VERSION 5.7 ;
  NOWIREEXTENSIONATPIN ON ;
  DIVIDERCHAR "/" ;
  BUSBITCHARS "[]" ;
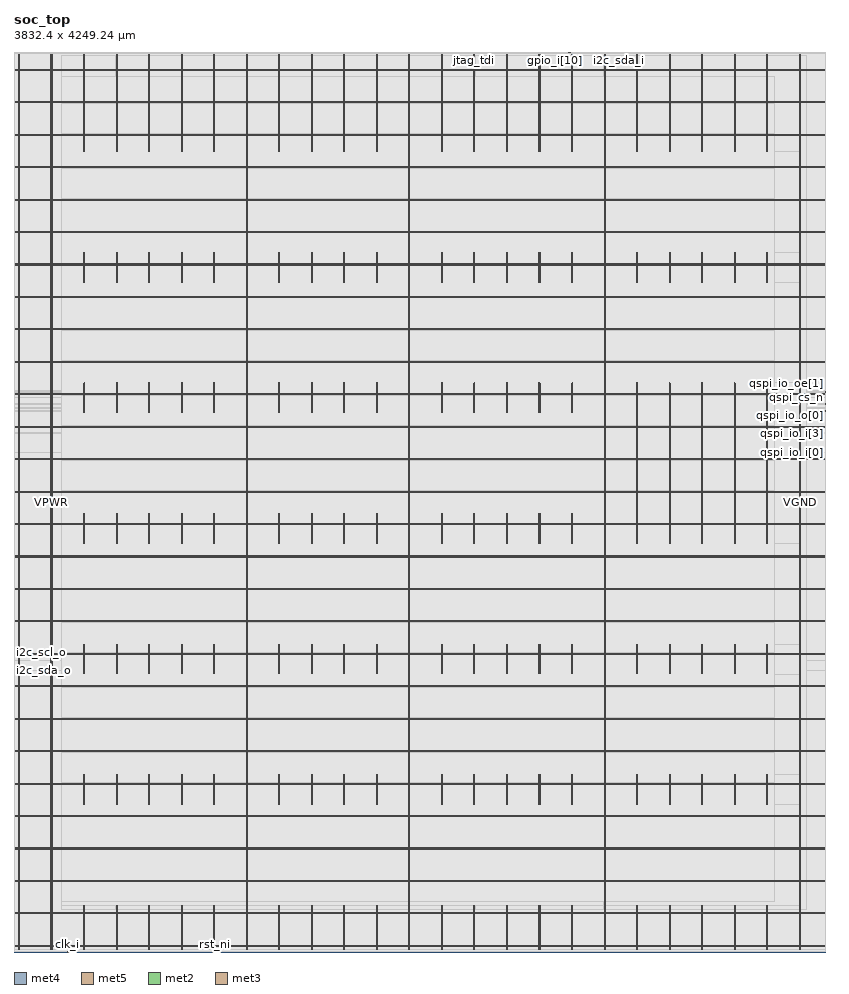
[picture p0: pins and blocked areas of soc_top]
MACRO soc_top
  CLASS BLOCK ;
  FOREIGN soc_top ;
  ORIGIN 0.000 0.000 ;
  SIZE 3832.400 BY 4249.240 ;
  PIN VGND
    DIRECTION INOUT ;
    USE GROUND ;
    PORT
      LAYER met4 ;
        RECT 24.340 10.640 25.940 4238.000 ;
    END
    PORT
      LAYER met4 ;
        RECT 177.940 10.640 179.540 4238.000 ;
    END
    PORT
      LAYER met4 ;
        RECT 331.540 10.640 333.140 220.320 ;
    END
    PORT
      LAYER met4 ;
        RECT 331.540 696.220 333.140 836.860 ;
    END
    PORT
      LAYER met4 ;
        RECT 331.540 1312.760 333.140 1453.400 ;
    END
    PORT
      LAYER met4 ;
        RECT 331.540 1929.300 333.140 2069.940 ;
    END
    PORT
      LAYER met4 ;
        RECT 331.540 2545.840 333.140 2686.480 ;
    END
    PORT
      LAYER met4 ;
        RECT 331.540 3162.380 333.140 3303.020 ;
    END
    PORT
      LAYER met4 ;
        RECT 331.540 3778.920 333.140 4238.000 ;
    END
    PORT
      LAYER met4 ;
        RECT 485.140 10.640 486.740 220.320 ;
    END
    PORT
      LAYER met4 ;
        RECT 485.140 696.220 486.740 836.860 ;
    END
    PORT
      LAYER met4 ;
        RECT 485.140 1312.760 486.740 1453.400 ;
    END
    PORT
      LAYER met4 ;
        RECT 485.140 1929.300 486.740 2069.940 ;
    END
    PORT
      LAYER met4 ;
        RECT 485.140 2545.840 486.740 2686.480 ;
    END
    PORT
      LAYER met4 ;
        RECT 485.140 3162.380 486.740 3303.020 ;
    END
    PORT
      LAYER met4 ;
        RECT 485.140 3778.920 486.740 4238.000 ;
    END
    PORT
      LAYER met4 ;
        RECT 638.740 10.640 640.340 220.320 ;
    END
    PORT
      LAYER met4 ;
        RECT 638.740 696.220 640.340 836.860 ;
    END
    PORT
      LAYER met4 ;
        RECT 638.740 1312.760 640.340 1453.400 ;
    END
    PORT
      LAYER met4 ;
        RECT 638.740 1929.300 640.340 2069.940 ;
    END
    PORT
      LAYER met4 ;
        RECT 638.740 2545.840 640.340 2686.480 ;
    END
    PORT
      LAYER met4 ;
        RECT 638.740 3162.380 640.340 3303.020 ;
    END
    PORT
      LAYER met4 ;
        RECT 638.740 3778.920 640.340 4238.000 ;
    END
    PORT
      LAYER met4 ;
        RECT 792.340 10.640 793.940 220.320 ;
    END
    PORT
      LAYER met4 ;
        RECT 792.340 696.220 793.940 836.860 ;
    END
    PORT
      LAYER met4 ;
        RECT 792.340 1312.760 793.940 1453.400 ;
    END
    PORT
      LAYER met4 ;
        RECT 792.340 1929.300 793.940 2069.940 ;
    END
    PORT
      LAYER met4 ;
        RECT 792.340 2545.840 793.940 2686.480 ;
    END
    PORT
      LAYER met4 ;
        RECT 792.340 3162.380 793.940 3303.020 ;
    END
    PORT
      LAYER met4 ;
        RECT 792.340 3778.920 793.940 4238.000 ;
    END
    PORT
      LAYER met4 ;
        RECT 945.940 10.640 947.540 220.320 ;
    END
    PORT
      LAYER met4 ;
        RECT 945.940 696.220 947.540 836.860 ;
    END
    PORT
      LAYER met4 ;
        RECT 945.940 1312.760 947.540 1453.400 ;
    END
    PORT
      LAYER met4 ;
        RECT 945.940 1929.300 947.540 2069.940 ;
    END
    PORT
      LAYER met4 ;
        RECT 945.940 2545.840 947.540 2686.480 ;
    END
    PORT
      LAYER met4 ;
        RECT 945.940 3162.380 947.540 3303.020 ;
    END
    PORT
      LAYER met4 ;
        RECT 945.940 3778.920 947.540 4238.000 ;
    END
    PORT
      LAYER met4 ;
        RECT 1099.540 10.640 1101.140 4238.000 ;
    END
    PORT
      LAYER met4 ;
        RECT 1253.140 10.640 1254.740 219.400 ;
    END
    PORT
      LAYER met4 ;
        RECT 1253.140 696.220 1254.740 835.940 ;
    END
    PORT
      LAYER met4 ;
        RECT 1253.140 1312.760 1254.740 1452.720 ;
    END
    PORT
      LAYER met4 ;
        RECT 1253.140 1929.300 1254.740 2069.020 ;
    END
    PORT
      LAYER met4 ;
        RECT 1253.140 2545.840 1254.740 2685.560 ;
    END
    PORT
      LAYER met4 ;
        RECT 1253.140 3162.380 1254.740 3302.320 ;
    END
    PORT
      LAYER met4 ;
        RECT 1253.140 3778.920 1254.740 4238.000 ;
    END
    PORT
      LAYER met4 ;
        RECT 1406.740 10.640 1408.340 220.320 ;
    END
    PORT
      LAYER met4 ;
        RECT 1406.740 696.220 1408.340 836.860 ;
    END
    PORT
      LAYER met4 ;
        RECT 1406.740 1312.760 1408.340 1453.400 ;
    END
    PORT
      LAYER met4 ;
        RECT 1406.740 1929.300 1408.340 2069.940 ;
    END
    PORT
      LAYER met4 ;
        RECT 1406.740 2545.840 1408.340 2686.480 ;
    END
    PORT
      LAYER met4 ;
        RECT 1406.740 3162.380 1408.340 3303.020 ;
    END
    PORT
      LAYER met4 ;
        RECT 1406.740 3778.920 1408.340 4238.000 ;
    END
    PORT
      LAYER met4 ;
        RECT 1560.340 10.640 1561.940 220.320 ;
    END
    PORT
      LAYER met4 ;
        RECT 1560.340 696.220 1561.940 836.860 ;
    END
    PORT
      LAYER met4 ;
        RECT 1560.340 1312.760 1561.940 1453.400 ;
    END
    PORT
      LAYER met4 ;
        RECT 1560.340 1929.300 1561.940 2069.940 ;
    END
    PORT
      LAYER met4 ;
        RECT 1560.340 2545.840 1561.940 2686.480 ;
    END
    PORT
      LAYER met4 ;
        RECT 1560.340 3162.380 1561.940 3303.020 ;
    END
    PORT
      LAYER met4 ;
        RECT 1560.340 3778.920 1561.940 4238.000 ;
    END
    PORT
      LAYER met4 ;
        RECT 1713.940 10.640 1715.540 220.320 ;
    END
    PORT
      LAYER met4 ;
        RECT 1713.940 696.220 1715.540 836.860 ;
    END
    PORT
      LAYER met4 ;
        RECT 1713.940 1312.760 1715.540 1453.400 ;
    END
    PORT
      LAYER met4 ;
        RECT 1713.940 1929.300 1715.540 2069.940 ;
    END
    PORT
      LAYER met4 ;
        RECT 1713.940 2545.840 1715.540 2686.480 ;
    END
    PORT
      LAYER met4 ;
        RECT 1713.940 3162.380 1715.540 3303.020 ;
    END
    PORT
      LAYER met4 ;
        RECT 1713.940 3778.920 1715.540 4238.000 ;
    END
    PORT
      LAYER met4 ;
        RECT 1867.540 10.640 1869.140 4238.000 ;
    END
    PORT
      LAYER met4 ;
        RECT 2021.140 10.640 2022.740 220.320 ;
    END
    PORT
      LAYER met4 ;
        RECT 2021.140 696.220 2022.740 836.860 ;
    END
    PORT
      LAYER met4 ;
        RECT 2021.140 1312.760 2022.740 1453.400 ;
    END
    PORT
      LAYER met4 ;
        RECT 2021.140 1929.300 2022.740 2069.940 ;
    END
    PORT
      LAYER met4 ;
        RECT 2021.140 2545.840 2022.740 2686.480 ;
    END
    PORT
      LAYER met4 ;
        RECT 2021.140 3162.380 2022.740 3303.020 ;
    END
    PORT
      LAYER met4 ;
        RECT 2021.140 3778.920 2022.740 4238.000 ;
    END
    PORT
      LAYER met4 ;
        RECT 2174.740 10.640 2176.340 220.320 ;
    END
    PORT
      LAYER met4 ;
        RECT 2174.740 696.220 2176.340 836.860 ;
    END
    PORT
      LAYER met4 ;
        RECT 2174.740 1312.760 2176.340 1453.400 ;
    END
    PORT
      LAYER met4 ;
        RECT 2174.740 1929.300 2176.340 2069.940 ;
    END
    PORT
      LAYER met4 ;
        RECT 2174.740 2545.840 2176.340 2686.480 ;
    END
    PORT
      LAYER met4 ;
        RECT 2174.740 3162.380 2176.340 3303.020 ;
    END
    PORT
      LAYER met4 ;
        RECT 2174.740 3778.920 2176.340 4238.000 ;
    END
    PORT
      LAYER met4 ;
        RECT 2328.340 10.640 2329.940 220.320 ;
    END
    PORT
      LAYER met4 ;
        RECT 2328.340 696.220 2329.940 836.860 ;
    END
    PORT
      LAYER met4 ;
        RECT 2328.340 1312.760 2329.940 1453.400 ;
    END
    PORT
      LAYER met4 ;
        RECT 2328.340 1929.300 2329.940 2069.940 ;
    END
    PORT
      LAYER met4 ;
        RECT 2328.340 2545.840 2329.940 2686.480 ;
    END
    PORT
      LAYER met4 ;
        RECT 2328.340 3162.380 2329.940 3303.020 ;
    END
    PORT
      LAYER met4 ;
        RECT 2328.340 3778.920 2329.940 4238.000 ;
    END
    PORT
      LAYER met4 ;
        RECT 2481.940 10.640 2483.540 219.400 ;
    END
    PORT
      LAYER met4 ;
        RECT 2481.940 697.140 2483.540 835.940 ;
    END
    PORT
      LAYER met4 ;
        RECT 2481.940 1313.680 2483.540 1452.720 ;
    END
    PORT
      LAYER met4 ;
        RECT 2481.940 1930.220 2483.540 2069.020 ;
    END
    PORT
      LAYER met4 ;
        RECT 2481.940 2546.760 2483.540 2685.560 ;
    END
    PORT
      LAYER met4 ;
        RECT 2481.940 3163.300 2483.540 3302.320 ;
    END
    PORT
      LAYER met4 ;
        RECT 2481.940 3779.840 2483.540 4238.000 ;
    END
    PORT
      LAYER met4 ;
        RECT 2635.540 10.640 2637.140 220.320 ;
    END
    PORT
      LAYER met4 ;
        RECT 2635.540 696.220 2637.140 836.860 ;
    END
    PORT
      LAYER met4 ;
        RECT 2635.540 1312.760 2637.140 1453.400 ;
    END
    PORT
      LAYER met4 ;
        RECT 2635.540 1929.300 2637.140 2069.940 ;
    END
    PORT
      LAYER met4 ;
        RECT 2635.540 2545.840 2637.140 2686.480 ;
    END
    PORT
      LAYER met4 ;
        RECT 2635.540 3162.380 2637.140 3303.020 ;
    END
    PORT
      LAYER met4 ;
        RECT 2635.540 3778.920 2637.140 4238.000 ;
    END
    PORT
      LAYER met4 ;
        RECT 2789.140 10.640 2790.740 4238.000 ;
    END
    PORT
      LAYER met4 ;
        RECT 2942.740 10.640 2944.340 220.320 ;
    END
    PORT
      LAYER met4 ;
        RECT 2942.740 696.220 2944.340 836.860 ;
    END
    PORT
      LAYER met4 ;
        RECT 2942.740 1312.760 2944.340 1453.400 ;
    END
    PORT
      LAYER met4 ;
        RECT 2942.740 1929.300 2944.340 2686.480 ;
    END
    PORT
      LAYER met4 ;
        RECT 2942.740 3162.380 2944.340 3303.020 ;
    END
    PORT
      LAYER met4 ;
        RECT 2942.740 3778.920 2944.340 4238.000 ;
    END
    PORT
      LAYER met4 ;
        RECT 3096.340 10.640 3097.940 219.400 ;
    END
    PORT
      LAYER met4 ;
        RECT 3096.340 696.220 3097.940 835.940 ;
    END
    PORT
      LAYER met4 ;
        RECT 3096.340 1312.760 3097.940 1452.720 ;
    END
    PORT
      LAYER met4 ;
        RECT 3096.340 1929.300 3097.940 2685.560 ;
    END
    PORT
      LAYER met4 ;
        RECT 3096.340 3162.380 3097.940 3302.320 ;
    END
    PORT
      LAYER met4 ;
        RECT 3096.340 3778.920 3097.940 4238.000 ;
    END
    PORT
      LAYER met4 ;
        RECT 3249.940 10.640 3251.540 220.320 ;
    END
    PORT
      LAYER met4 ;
        RECT 3249.940 696.220 3251.540 836.860 ;
    END
    PORT
      LAYER met4 ;
        RECT 3249.940 1312.760 3251.540 1453.400 ;
    END
    PORT
      LAYER met4 ;
        RECT 3249.940 1929.300 3251.540 2686.480 ;
    END
    PORT
      LAYER met4 ;
        RECT 3249.940 3162.380 3251.540 3303.020 ;
    END
    PORT
      LAYER met4 ;
        RECT 3249.940 3778.920 3251.540 4238.000 ;
    END
    PORT
      LAYER met4 ;
        RECT 3403.540 10.640 3405.140 219.400 ;
    END
    PORT
      LAYER met4 ;
        RECT 3403.540 697.140 3405.140 835.940 ;
    END
    PORT
      LAYER met4 ;
        RECT 3403.540 1313.680 3405.140 1452.720 ;
    END
    PORT
      LAYER met4 ;
        RECT 3403.540 1930.220 3405.140 2685.560 ;
    END
    PORT
      LAYER met4 ;
        RECT 3403.540 3163.300 3405.140 3302.320 ;
    END
    PORT
      LAYER met4 ;
        RECT 3403.540 3779.840 3405.140 4238.000 ;
    END
    PORT
      LAYER met4 ;
        RECT 3557.140 10.640 3558.740 220.320 ;
    END
    PORT
      LAYER met4 ;
        RECT 3557.140 696.220 3558.740 836.860 ;
    END
    PORT
      LAYER met4 ;
        RECT 3557.140 1312.760 3558.740 1453.400 ;
    END
    PORT
      LAYER met4 ;
        RECT 3557.140 1929.300 3558.740 2686.480 ;
    END
    PORT
      LAYER met4 ;
        RECT 3557.140 3162.380 3558.740 3303.020 ;
    END
    PORT
      LAYER met4 ;
        RECT 3557.140 3778.920 3558.740 4238.000 ;
    END
    PORT
      LAYER met4 ;
        RECT 3710.740 10.640 3712.340 4238.000 ;
    END
    PORT
      LAYER met5 ;
        RECT 5.520 30.030 3826.740 31.630 ;
    END
    PORT
      LAYER met5 ;
        RECT 5.520 183.210 3826.740 184.810 ;
    END
    PORT
      LAYER met5 ;
        RECT 5.520 336.390 3826.740 337.990 ;
    END
    PORT
      LAYER met5 ;
        RECT 5.520 489.570 3826.740 491.170 ;
    END
    PORT
      LAYER met5 ;
        RECT 5.520 642.750 3826.740 644.350 ;
    END
    PORT
      LAYER met5 ;
        RECT 5.520 795.930 3826.740 797.530 ;
    END
    PORT
      LAYER met5 ;
        RECT 5.520 949.110 3826.740 950.710 ;
    END
    PORT
      LAYER met5 ;
        RECT 5.520 1102.290 3826.740 1103.890 ;
    END
    PORT
      LAYER met5 ;
        RECT 5.520 1255.470 3826.740 1257.070 ;
    END
    PORT
      LAYER met5 ;
        RECT 5.520 1408.650 3826.740 1410.250 ;
    END
    PORT
      LAYER met5 ;
        RECT 5.520 1561.830 3826.740 1563.430 ;
    END
    PORT
      LAYER met5 ;
        RECT 5.520 1715.010 3826.740 1716.610 ;
    END
    PORT
      LAYER met5 ;
        RECT 5.520 1868.190 3826.740 1869.790 ;
    END
    PORT
      LAYER met5 ;
        RECT 5.520 2021.370 3826.740 2022.970 ;
    END
    PORT
      LAYER met5 ;
        RECT 5.520 2174.550 3826.740 2176.150 ;
    END
    PORT
      LAYER met5 ;
        RECT 5.520 2327.730 3826.740 2329.330 ;
    END
    PORT
      LAYER met5 ;
        RECT 5.520 2480.910 3826.740 2482.510 ;
    END
    PORT
      LAYER met5 ;
        RECT 5.520 2634.090 3826.740 2635.690 ;
    END
    PORT
      LAYER met5 ;
        RECT 5.520 2787.270 3826.740 2788.870 ;
    END
    PORT
      LAYER met5 ;
        RECT 5.520 2940.450 3826.740 2942.050 ;
    END
    PORT
      LAYER met5 ;
        RECT 5.520 3093.630 3826.740 3095.230 ;
    END
    PORT
      LAYER met5 ;
        RECT 5.520 3246.810 3826.740 3248.410 ;
    END
    PORT
      LAYER met5 ;
        RECT 5.520 3399.990 3826.740 3401.590 ;
    END
    PORT
      LAYER met5 ;
        RECT 5.520 3553.170 3826.740 3554.770 ;
    END
    PORT
      LAYER met5 ;
        RECT 5.520 3706.350 3826.740 3707.950 ;
    END
    PORT
      LAYER met5 ;
        RECT 5.520 3859.530 3826.740 3861.130 ;
    END
    PORT
      LAYER met5 ;
        RECT 5.520 4012.710 3826.740 4014.310 ;
    END
    PORT
      LAYER met5 ;
        RECT 5.520 4165.890 3826.740 4167.490 ;
    END
  END VGND
  PIN VPWR
    DIRECTION INOUT ;
    USE POWER ;
    PORT
      LAYER met4 ;
        RECT 21.040 10.640 22.640 4238.000 ;
    END
    PORT
      LAYER met4 ;
        RECT 174.640 10.640 176.240 4238.000 ;
    END
    PORT
      LAYER met4 ;
        RECT 328.240 10.640 329.840 219.400 ;
    END
    PORT
      LAYER met4 ;
        RECT 328.240 696.220 329.840 835.940 ;
    END
    PORT
      LAYER met4 ;
        RECT 328.240 1312.760 329.840 1452.480 ;
    END
    PORT
      LAYER met4 ;
        RECT 328.240 1929.300 329.840 2069.020 ;
    END
    PORT
      LAYER met4 ;
        RECT 328.240 2545.840 329.840 2685.560 ;
    END
    PORT
      LAYER met4 ;
        RECT 328.240 3162.380 329.840 3302.100 ;
    END
    PORT
      LAYER met4 ;
        RECT 328.240 3778.920 329.840 4238.000 ;
    END
    PORT
      LAYER met4 ;
        RECT 481.840 10.640 483.440 219.400 ;
    END
    PORT
      LAYER met4 ;
        RECT 481.840 696.220 483.440 835.940 ;
    END
    PORT
      LAYER met4 ;
        RECT 481.840 1312.760 483.440 1452.480 ;
    END
    PORT
      LAYER met4 ;
        RECT 481.840 1929.300 483.440 2069.020 ;
    END
    PORT
      LAYER met4 ;
        RECT 481.840 2545.840 483.440 2685.560 ;
    END
    PORT
      LAYER met4 ;
        RECT 481.840 3162.380 483.440 3302.100 ;
    END
    PORT
      LAYER met4 ;
        RECT 481.840 3778.920 483.440 4238.000 ;
    END
    PORT
      LAYER met4 ;
        RECT 635.440 10.640 637.040 220.320 ;
    END
    PORT
      LAYER met4 ;
        RECT 635.440 696.220 637.040 836.860 ;
    END
    PORT
      LAYER met4 ;
        RECT 635.440 1312.760 637.040 1453.400 ;
    END
    PORT
      LAYER met4 ;
        RECT 635.440 1929.300 637.040 2069.940 ;
    END
    PORT
      LAYER met4 ;
        RECT 635.440 2545.840 637.040 2686.480 ;
    END
    PORT
      LAYER met4 ;
        RECT 635.440 3162.380 637.040 3303.020 ;
    END
    PORT
      LAYER met4 ;
        RECT 635.440 3778.920 637.040 4238.000 ;
    END
    PORT
      LAYER met4 ;
        RECT 789.040 10.640 790.640 220.320 ;
    END
    PORT
      LAYER met4 ;
        RECT 789.040 696.220 790.640 836.860 ;
    END
    PORT
      LAYER met4 ;
        RECT 789.040 1312.760 790.640 1453.400 ;
    END
    PORT
      LAYER met4 ;
        RECT 789.040 1929.300 790.640 2069.940 ;
    END
    PORT
      LAYER met4 ;
        RECT 789.040 2545.840 790.640 2686.480 ;
    END
    PORT
      LAYER met4 ;
        RECT 789.040 3162.380 790.640 3303.020 ;
    END
    PORT
      LAYER met4 ;
        RECT 789.040 3778.920 790.640 4238.000 ;
    END
    PORT
      LAYER met4 ;
        RECT 942.640 10.640 944.240 220.320 ;
    END
    PORT
      LAYER met4 ;
        RECT 942.640 696.220 944.240 836.860 ;
    END
    PORT
      LAYER met4 ;
        RECT 942.640 1312.760 944.240 1453.400 ;
    END
    PORT
      LAYER met4 ;
        RECT 942.640 1929.300 944.240 2069.940 ;
    END
    PORT
      LAYER met4 ;
        RECT 942.640 2545.840 944.240 2686.480 ;
    END
    PORT
      LAYER met4 ;
        RECT 942.640 3162.380 944.240 3303.020 ;
    END
    PORT
      LAYER met4 ;
        RECT 942.640 3778.920 944.240 4238.000 ;
    END
    PORT
      LAYER met4 ;
        RECT 1096.240 10.640 1097.840 4238.000 ;
    END
    PORT
      LAYER met4 ;
        RECT 1249.840 10.640 1251.440 220.320 ;
    END
    PORT
      LAYER met4 ;
        RECT 1249.840 696.220 1251.440 836.860 ;
    END
    PORT
      LAYER met4 ;
        RECT 1249.840 1312.760 1251.440 1453.400 ;
    END
    PORT
      LAYER met4 ;
        RECT 1249.840 1929.300 1251.440 2069.940 ;
    END
    PORT
      LAYER met4 ;
        RECT 1249.840 2545.840 1251.440 2686.480 ;
    END
    PORT
      LAYER met4 ;
        RECT 1249.840 3162.380 1251.440 3303.020 ;
    END
    PORT
      LAYER met4 ;
        RECT 1249.840 3778.920 1251.440 4238.000 ;
    END
    PORT
      LAYER met4 ;
        RECT 1403.440 10.640 1405.040 219.400 ;
    END
    PORT
      LAYER met4 ;
        RECT 1403.440 696.220 1405.040 835.940 ;
    END
    PORT
      LAYER met4 ;
        RECT 1403.440 1312.760 1405.040 1452.480 ;
    END
    PORT
      LAYER met4 ;
        RECT 1403.440 1929.300 1405.040 2069.020 ;
    END
    PORT
      LAYER met4 ;
        RECT 1403.440 2545.840 1405.040 2685.560 ;
    END
    PORT
      LAYER met4 ;
        RECT 1403.440 3162.380 1405.040 3302.100 ;
    END
    PORT
      LAYER met4 ;
        RECT 1403.440 3778.920 1405.040 4238.000 ;
    END
    PORT
      LAYER met4 ;
        RECT 1557.040 10.640 1558.640 220.320 ;
    END
    PORT
      LAYER met4 ;
        RECT 1557.040 696.220 1558.640 836.860 ;
    END
    PORT
      LAYER met4 ;
        RECT 1557.040 1312.760 1558.640 1453.400 ;
    END
    PORT
      LAYER met4 ;
        RECT 1557.040 1929.300 1558.640 2069.940 ;
    END
    PORT
      LAYER met4 ;
        RECT 1557.040 2545.840 1558.640 2686.480 ;
    END
    PORT
      LAYER met4 ;
        RECT 1557.040 3162.380 1558.640 3303.020 ;
    END
    PORT
      LAYER met4 ;
        RECT 1557.040 3778.920 1558.640 4238.000 ;
    END
    PORT
      LAYER met4 ;
        RECT 1710.640 10.640 1712.240 220.320 ;
    END
    PORT
      LAYER met4 ;
        RECT 1710.640 696.220 1712.240 836.860 ;
    END
    PORT
      LAYER met4 ;
        RECT 1710.640 1312.760 1712.240 1453.400 ;
    END
    PORT
      LAYER met4 ;
        RECT 1710.640 1929.300 1712.240 2069.940 ;
    END
    PORT
      LAYER met4 ;
        RECT 1710.640 2545.840 1712.240 2686.480 ;
    END
    PORT
      LAYER met4 ;
        RECT 1710.640 3162.380 1712.240 3303.020 ;
    END
    PORT
      LAYER met4 ;
        RECT 1710.640 3778.920 1712.240 4238.000 ;
    END
    PORT
      LAYER met4 ;
        RECT 1864.240 10.640 1865.840 4238.000 ;
    END
    PORT
      LAYER met4 ;
        RECT 2017.840 10.640 2019.440 220.320 ;
    END
    PORT
      LAYER met4 ;
        RECT 2017.840 696.220 2019.440 836.860 ;
    END
    PORT
      LAYER met4 ;
        RECT 2017.840 1312.760 2019.440 1453.400 ;
    END
    PORT
      LAYER met4 ;
        RECT 2017.840 1929.300 2019.440 2069.940 ;
    END
    PORT
      LAYER met4 ;
        RECT 2017.840 2545.840 2019.440 2686.480 ;
    END
    PORT
      LAYER met4 ;
        RECT 2017.840 3162.380 2019.440 3303.020 ;
    END
    PORT
      LAYER met4 ;
        RECT 2017.840 3778.920 2019.440 4238.000 ;
    END
    PORT
      LAYER met4 ;
        RECT 2171.440 10.640 2173.040 219.400 ;
    END
    PORT
      LAYER met4 ;
        RECT 2171.440 697.140 2173.040 835.940 ;
    END
    PORT
      LAYER met4 ;
        RECT 2171.440 1313.520 2173.040 1452.480 ;
    END
    PORT
      LAYER met4 ;
        RECT 2171.440 1930.220 2173.040 2069.020 ;
    END
    PORT
      LAYER met4 ;
        RECT 2171.440 2546.760 2173.040 2685.560 ;
    END
    PORT
      LAYER met4 ;
        RECT 2171.440 3163.120 2173.040 3302.100 ;
    END
    PORT
      LAYER met4 ;
        RECT 2171.440 3779.840 2173.040 4238.000 ;
    END
    PORT
      LAYER met4 ;
        RECT 2325.040 10.640 2326.640 220.320 ;
    END
    PORT
      LAYER met4 ;
        RECT 2325.040 696.220 2326.640 836.860 ;
    END
    PORT
      LAYER met4 ;
        RECT 2325.040 1312.760 2326.640 1453.400 ;
    END
    PORT
      LAYER met4 ;
        RECT 2325.040 1929.300 2326.640 2069.940 ;
    END
    PORT
      LAYER met4 ;
        RECT 2325.040 2545.840 2326.640 2686.480 ;
    END
    PORT
      LAYER met4 ;
        RECT 2325.040 3162.380 2326.640 3303.020 ;
    END
    PORT
      LAYER met4 ;
        RECT 2325.040 3778.920 2326.640 4238.000 ;
    END
    PORT
      LAYER met4 ;
        RECT 2478.640 10.640 2480.240 220.320 ;
    END
    PORT
      LAYER met4 ;
        RECT 2478.640 696.220 2480.240 836.860 ;
    END
    PORT
      LAYER met4 ;
        RECT 2478.640 1312.760 2480.240 1453.400 ;
    END
    PORT
      LAYER met4 ;
        RECT 2478.640 1929.300 2480.240 2069.940 ;
    END
    PORT
      LAYER met4 ;
        RECT 2478.640 2545.840 2480.240 2686.480 ;
    END
    PORT
      LAYER met4 ;
        RECT 2478.640 3162.380 2480.240 3303.020 ;
    END
    PORT
      LAYER met4 ;
        RECT 2478.640 3778.920 2480.240 4238.000 ;
    END
    PORT
      LAYER met4 ;
        RECT 2632.240 10.640 2633.840 219.400 ;
    END
    PORT
      LAYER met4 ;
        RECT 2632.240 696.220 2633.840 835.940 ;
    END
    PORT
      LAYER met4 ;
        RECT 2632.240 1312.760 2633.840 1452.480 ;
    END
    PORT
      LAYER met4 ;
        RECT 2632.240 1929.300 2633.840 2069.020 ;
    END
    PORT
      LAYER met4 ;
        RECT 2632.240 2545.840 2633.840 2685.560 ;
    END
    PORT
      LAYER met4 ;
        RECT 2632.240 3162.380 2633.840 3302.100 ;
    END
    PORT
      LAYER met4 ;
        RECT 2632.240 3778.920 2633.840 4238.000 ;
    END
    PORT
      LAYER met4 ;
        RECT 2785.840 10.640 2787.440 4238.000 ;
    END
    PORT
      LAYER met4 ;
        RECT 2939.440 10.640 2941.040 220.320 ;
    END
    PORT
      LAYER met4 ;
        RECT 2939.440 696.220 2941.040 836.860 ;
    END
    PORT
      LAYER met4 ;
        RECT 2939.440 1312.760 2941.040 1453.400 ;
    END
    PORT
      LAYER met4 ;
        RECT 2939.440 1929.300 2941.040 2686.480 ;
    END
    PORT
      LAYER met4 ;
        RECT 2939.440 3162.380 2941.040 3303.020 ;
    END
    PORT
      LAYER met4 ;
        RECT 2939.440 3778.920 2941.040 4238.000 ;
    END
    PORT
      LAYER met4 ;
        RECT 3093.040 10.640 3094.640 220.320 ;
    END
    PORT
      LAYER met4 ;
        RECT 3093.040 696.220 3094.640 836.860 ;
    END
    PORT
      LAYER met4 ;
        RECT 3093.040 1312.760 3094.640 1453.400 ;
    END
    PORT
      LAYER met4 ;
        RECT 3093.040 1929.300 3094.640 2686.480 ;
    END
    PORT
      LAYER met4 ;
        RECT 3093.040 3162.380 3094.640 3303.020 ;
    END
    PORT
      LAYER met4 ;
        RECT 3093.040 3778.920 3094.640 4238.000 ;
    END
    PORT
      LAYER met4 ;
        RECT 3246.640 10.640 3248.240 220.320 ;
    END
    PORT
      LAYER met4 ;
        RECT 3246.640 696.220 3248.240 836.860 ;
    END
    PORT
      LAYER met4 ;
        RECT 3246.640 1312.760 3248.240 1453.400 ;
    END
    PORT
      LAYER met4 ;
        RECT 3246.640 1929.300 3248.240 2686.480 ;
    END
    PORT
      LAYER met4 ;
        RECT 3246.640 3162.380 3248.240 3303.020 ;
    END
    PORT
      LAYER met4 ;
        RECT 3246.640 3778.920 3248.240 4238.000 ;
    END
    PORT
      LAYER met4 ;
        RECT 3400.240 10.640 3401.840 220.320 ;
    END
    PORT
      LAYER met4 ;
        RECT 3400.240 696.220 3401.840 836.860 ;
    END
    PORT
      LAYER met4 ;
        RECT 3400.240 1312.760 3401.840 1453.400 ;
    END
    PORT
      LAYER met4 ;
        RECT 3400.240 1929.300 3401.840 2686.480 ;
    END
    PORT
      LAYER met4 ;
        RECT 3400.240 3162.380 3401.840 3303.020 ;
    END
    PORT
      LAYER met4 ;
        RECT 3400.240 3778.920 3401.840 4238.000 ;
    END
    PORT
      LAYER met4 ;
        RECT 3553.840 10.640 3555.440 220.320 ;
    END
    PORT
      LAYER met4 ;
        RECT 3553.840 697.140 3555.440 836.860 ;
    END
    PORT
      LAYER met4 ;
        RECT 3553.840 1313.520 3555.440 1453.400 ;
    END
    PORT
      LAYER met4 ;
        RECT 3553.840 1930.220 3555.440 2686.480 ;
    END
    PORT
      LAYER met4 ;
        RECT 3553.840 3163.120 3555.440 3303.020 ;
    END
    PORT
      LAYER met4 ;
        RECT 3553.840 3779.840 3555.440 4238.000 ;
    END
    PORT
      LAYER met4 ;
        RECT 3707.440 10.640 3709.040 4238.000 ;
    END
    PORT
      LAYER met5 ;
        RECT 5.520 26.730 3826.740 28.330 ;
    END
    PORT
      LAYER met5 ;
        RECT 5.520 179.910 3826.740 181.510 ;
    END
    PORT
      LAYER met5 ;
        RECT 5.520 333.090 3826.740 334.690 ;
    END
    PORT
      LAYER met5 ;
        RECT 5.520 486.270 3826.740 487.870 ;
    END
    PORT
      LAYER met5 ;
        RECT 5.520 639.450 3826.740 641.050 ;
    END
    PORT
      LAYER met5 ;
        RECT 5.520 792.630 3826.740 794.230 ;
    END
    PORT
      LAYER met5 ;
        RECT 5.520 945.810 3826.740 947.410 ;
    END
    PORT
      LAYER met5 ;
        RECT 5.520 1098.990 3826.740 1100.590 ;
    END
    PORT
      LAYER met5 ;
        RECT 5.520 1252.170 3826.740 1253.770 ;
    END
    PORT
      LAYER met5 ;
        RECT 5.520 1405.350 3826.740 1406.950 ;
    END
    PORT
      LAYER met5 ;
        RECT 5.520 1558.530 3826.740 1560.130 ;
    END
    PORT
      LAYER met5 ;
        RECT 5.520 1711.710 3826.740 1713.310 ;
    END
    PORT
      LAYER met5 ;
        RECT 5.520 1864.890 3826.740 1866.490 ;
    END
    PORT
      LAYER met5 ;
        RECT 5.520 2018.070 3826.740 2019.670 ;
    END
    PORT
      LAYER met5 ;
        RECT 5.520 2171.250 3826.740 2172.850 ;
    END
    PORT
      LAYER met5 ;
        RECT 5.520 2324.430 3826.740 2326.030 ;
    END
    PORT
      LAYER met5 ;
        RECT 5.520 2477.610 3826.740 2479.210 ;
    END
    PORT
      LAYER met5 ;
        RECT 5.520 2630.790 3826.740 2632.390 ;
    END
    PORT
      LAYER met5 ;
        RECT 5.520 2783.970 3826.740 2785.570 ;
    END
    PORT
      LAYER met5 ;
        RECT 5.520 2937.150 3826.740 2938.750 ;
    END
    PORT
      LAYER met5 ;
        RECT 5.520 3090.330 3826.740 3091.930 ;
    END
    PORT
      LAYER met5 ;
        RECT 5.520 3243.510 3826.740 3245.110 ;
    END
    PORT
      LAYER met5 ;
        RECT 5.520 3396.690 3826.740 3398.290 ;
    END
    PORT
      LAYER met5 ;
        RECT 5.520 3549.870 3826.740 3551.470 ;
    END
    PORT
      LAYER met5 ;
        RECT 5.520 3703.050 3826.740 3704.650 ;
    END
    PORT
      LAYER met5 ;
        RECT 5.520 3856.230 3826.740 3857.830 ;
    END
    PORT
      LAYER met5 ;
        RECT 5.520 4009.410 3826.740 4011.010 ;
    END
    PORT
      LAYER met5 ;
        RECT 5.520 4162.590 3826.740 4164.190 ;
    END
  END VPWR
  PIN clk_i
    DIRECTION INPUT ;
    USE SIGNAL ;
    ANTENNAGATEAREA 2.573400 ;
    ANTENNADIFFAREA 0.869400 ;
    PORT
      LAYER met2 ;
        RECT 251.250 0.000 251.530 0.280 ;
    END
  END clk_i
  PIN gpio_i[0]
    DIRECTION INPUT ;
    USE SIGNAL ;
    ANTENNAGATEAREA 0.126000 ;
    PORT
      LAYER met2 ;
        RECT 2577.930 4248.960 2578.210 4249.240 ;
    END
  END gpio_i[0]
  PIN gpio_i[10]
    DIRECTION INPUT ;
    USE SIGNAL ;
    ANTENNAGATEAREA 0.126000 ;
    PORT
      LAYER met2 ;
        RECT 2553.090 4248.960 2553.370 4249.240 ;
    END
  END gpio_i[10]
  PIN gpio_i[11]
    DIRECTION INPUT ;
    USE SIGNAL ;
    ANTENNAGATEAREA 0.126000 ;
    PORT
      LAYER met2 ;
        RECT 2628.530 4248.960 2628.810 4249.240 ;
    END
  END gpio_i[11]
  PIN gpio_i[12]
    DIRECTION INPUT ;
    USE SIGNAL ;
    ANTENNAGATEAREA 0.126000 ;
    PORT
      LAYER met2 ;
        RECT 2534.690 4248.960 2534.970 4249.240 ;
    END
  END gpio_i[12]
  PIN gpio_i[13]
    DIRECTION INPUT ;
    USE SIGNAL ;
    ANTENNAGATEAREA 0.126000 ;
    PORT
      LAYER met2 ;
        RECT 2614.730 4248.960 2615.010 4249.240 ;
    END
  END gpio_i[13]
  PIN gpio_i[14]
    DIRECTION INPUT ;
    USE SIGNAL ;
    ANTENNAGATEAREA 0.126000 ;
    PORT
      LAYER met2 ;
        RECT 2626.690 4248.960 2626.970 4249.240 ;
    END
  END gpio_i[14]
  PIN gpio_i[15]
    DIRECTION INPUT ;
    USE SIGNAL ;
    ANTENNAGATEAREA 0.126000 ;
    PORT
      LAYER met2 ;
        RECT 2525.490 4248.960 2525.770 4249.240 ;
    END
  END gpio_i[15]
  PIN gpio_i[1]
    DIRECTION INPUT ;
    USE SIGNAL ;
    ANTENNAGATEAREA 0.126000 ;
    PORT
      LAYER met2 ;
        RECT 2655.210 4248.960 2655.490 4249.240 ;
    END
  END gpio_i[1]
  PIN gpio_i[2]
    DIRECTION INPUT ;
    USE SIGNAL ;
    ANTENNAGATEAREA 0.126000 ;
    PORT
      LAYER met2 ;
        RECT 2675.450 4248.960 2675.730 4249.240 ;
    END
  END gpio_i[2]
  PIN gpio_i[3]
    DIRECTION INPUT ;
    USE SIGNAL ;
    ANTENNAGATEAREA 0.126000 ;
    PORT
      LAYER met2 ;
        RECT 2712.250 4248.960 2712.530 4249.240 ;
    END
  END gpio_i[3]
  PIN gpio_i[4]
    DIRECTION INPUT ;
    USE SIGNAL ;
    ANTENNAGATEAREA 0.126000 ;
    PORT
      LAYER met2 ;
        RECT 2715.010 4248.960 2715.290 4249.240 ;
    END
  END gpio_i[4]
  PIN gpio_i[5]
    DIRECTION INPUT ;
    USE SIGNAL ;
    ANTENNAGATEAREA 0.126000 ;
    PORT
      LAYER met2 ;
        RECT 2611.050 4248.960 2611.330 4249.240 ;
    END
  END gpio_i[5]
  PIN gpio_i[6]
    DIRECTION INPUT ;
    USE SIGNAL ;
    ANTENNAGATEAREA 0.126000 ;
    PORT
      LAYER met2 ;
        RECT 2649.690 4248.960 2649.970 4249.240 ;
    END
  END gpio_i[6]
  PIN gpio_i[7]
    DIRECTION INPUT ;
    USE SIGNAL ;
    ANTENNAGATEAREA 0.126000 ;
    PORT
      LAYER met2 ;
        RECT 2629.450 4248.960 2629.730 4249.240 ;
    END
  END gpio_i[7]
  PIN gpio_i[8]
    DIRECTION INPUT ;
    USE SIGNAL ;
    ANTENNAGATEAREA 0.126000 ;
    PORT
      LAYER met2 ;
        RECT 2574.250 4248.960 2574.530 4249.240 ;
    END
  END gpio_i[8]
  PIN gpio_i[9]
    DIRECTION INPUT ;
    USE SIGNAL ;
    ANTENNAGATEAREA 0.126000 ;
    PORT
      LAYER met2 ;
        RECT 2579.770 4248.960 2580.050 4249.240 ;
    END
  END gpio_i[9]
  PIN gpio_o[0]
    DIRECTION OUTPUT ;
    USE SIGNAL ;
    ANTENNADIFFAREA 0.702900 ;
    PORT
      LAYER met2 ;
        RECT 2608.290 4248.960 2608.570 4249.240 ;
    END
  END gpio_o[0]
  PIN gpio_o[10]
    DIRECTION OUTPUT ;
    USE SIGNAL ;
    ANTENNADIFFAREA 0.702900 ;
    PORT
      LAYER met2 ;
        RECT 2542.050 4248.960 2542.330 4249.240 ;
    END
  END gpio_o[10]
  PIN gpio_o[11]
    DIRECTION OUTPUT ;
    USE SIGNAL ;
    ANTENNADIFFAREA 0.702900 ;
    PORT
      LAYER met2 ;
        RECT 2631.290 4248.960 2631.570 4249.240 ;
    END
  END gpio_o[11]
  PIN gpio_o[12]
    DIRECTION OUTPUT ;
    USE SIGNAL ;
    ANTENNADIFFAREA 0.702900 ;
    PORT
      LAYER met2 ;
        RECT 2541.130 4248.960 2541.410 4249.240 ;
    END
  END gpio_o[12]
  PIN gpio_o[13]
    DIRECTION OUTPUT ;
    USE SIGNAL ;
    ANTENNADIFFAREA 0.702900 ;
    PORT
      LAYER met2 ;
        RECT 2619.330 4248.960 2619.610 4249.240 ;
    END
  END gpio_o[13]
  PIN gpio_o[14]
    DIRECTION OUTPUT ;
    USE SIGNAL ;
    ANTENNADIFFAREA 0.702900 ;
    PORT
      LAYER met2 ;
        RECT 2648.770 4248.960 2649.050 4249.240 ;
    END
  END gpio_o[14]
  PIN gpio_o[15]
    DIRECTION OUTPUT ;
    USE SIGNAL ;
    ANTENNADIFFAREA 0.702900 ;
    PORT
      LAYER met2 ;
        RECT 2576.090 4248.960 2576.370 4249.240 ;
    END
  END gpio_o[15]
  PIN gpio_o[1]
    DIRECTION OUTPUT ;
    USE SIGNAL ;
    ANTENNADIFFAREA 0.702900 ;
    PORT
      LAYER met2 ;
        RECT 2676.370 4248.960 2676.650 4249.240 ;
    END
  END gpio_o[1]
  PIN gpio_o[2]
    DIRECTION OUTPUT ;
    USE SIGNAL ;
    ANTENNADIFFAREA 0.702900 ;
    PORT
      LAYER met2 ;
        RECT 2677.290 4248.960 2677.570 4249.240 ;
    END
  END gpio_o[2]
  PIN gpio_o[3]
    DIRECTION OUTPUT ;
    USE SIGNAL ;
    ANTENNADIFFAREA 0.702900 ;
    PORT
      LAYER met2 ;
        RECT 2682.810 4248.960 2683.090 4249.240 ;
    END
  END gpio_o[3]
  PIN gpio_o[4]
    DIRECTION OUTPUT ;
    USE SIGNAL ;
    ANTENNADIFFAREA 0.702900 ;
    PORT
      LAYER met2 ;
        RECT 2674.530 4248.960 2674.810 4249.240 ;
    END
  END gpio_o[4]
  PIN gpio_o[5]
    DIRECTION OUTPUT ;
    USE SIGNAL ;
    ANTENNADIFFAREA 0.702900 ;
    PORT
      LAYER met2 ;
        RECT 2623.930 4248.960 2624.210 4249.240 ;
    END
  END gpio_o[5]
  PIN gpio_o[6]
    DIRECTION OUTPUT ;
    USE SIGNAL ;
    ANTENNADIFFAREA 0.702900 ;
    PORT
      LAYER met2 ;
        RECT 2665.330 4248.960 2665.610 4249.240 ;
    END
  END gpio_o[6]
  PIN gpio_o[7]
    DIRECTION OUTPUT ;
    USE SIGNAL ;
    ANTENNADIFFAREA 0.702900 ;
    PORT
      LAYER met2 ;
        RECT 2660.730 4248.960 2661.010 4249.240 ;
    END
  END gpio_o[7]
  PIN gpio_o[8]
    DIRECTION OUTPUT ;
    USE SIGNAL ;
    ANTENNADIFFAREA 0.702900 ;
    PORT
      LAYER met2 ;
        RECT 2590.810 4248.960 2591.090 4249.240 ;
    END
  END gpio_o[8]
  PIN gpio_o[9]
    DIRECTION OUTPUT ;
    USE SIGNAL ;
    ANTENNADIFFAREA 0.702900 ;
    PORT
      LAYER met2 ;
        RECT 2594.490 4248.960 2594.770 4249.240 ;
    END
  END gpio_o[9]
  PIN gpio_tx_en_o[0]
    DIRECTION OUTPUT ;
    USE SIGNAL ;
    ANTENNADIFFAREA 0.702900 ;
    PORT
      LAYER met2 ;
        RECT 2611.970 4248.960 2612.250 4249.240 ;
    END
  END gpio_tx_en_o[0]
  PIN gpio_tx_en_o[10]
    DIRECTION OUTPUT ;
    USE SIGNAL ;
    ANTENNADIFFAREA 0.702900 ;
    PORT
      LAYER met2 ;
        RECT 2505.250 4248.960 2505.530 4249.240 ;
    END
  END gpio_tx_en_o[10]
  PIN gpio_tx_en_o[11]
    DIRECTION OUTPUT ;
    USE SIGNAL ;
    ANTENNADIFFAREA 0.702900 ;
    PORT
      LAYER met2 ;
        RECT 2509.850 4248.960 2510.130 4249.240 ;
    END
  END gpio_tx_en_o[11]
  PIN gpio_tx_en_o[12]
    DIRECTION OUTPUT ;
    USE SIGNAL ;
    ANTENNADIFFAREA 0.702900 ;
    PORT
      LAYER met2 ;
        RECT 2484.090 4248.960 2484.370 4249.240 ;
    END
  END gpio_tx_en_o[12]
  PIN gpio_tx_en_o[13]
    DIRECTION OUTPUT ;
    USE SIGNAL ;
    ANTENNADIFFAREA 0.702900 ;
    PORT
      LAYER met2 ;
        RECT 2526.410 4248.960 2526.690 4249.240 ;
    END
  END gpio_tx_en_o[13]
  PIN gpio_tx_en_o[14]
    DIRECTION OUTPUT ;
    USE SIGNAL ;
    ANTENNADIFFAREA 0.702900 ;
    PORT
      LAYER met2 ;
        RECT 2485.930 4248.960 2486.210 4249.240 ;
    END
  END gpio_tx_en_o[14]
  PIN gpio_tx_en_o[15]
    DIRECTION OUTPUT ;
    USE SIGNAL ;
    ANTENNADIFFAREA 0.702900 ;
    PORT
      LAYER met2 ;
        RECT 2536.530 4248.960 2536.810 4249.240 ;
    END
  END gpio_tx_en_o[15]
  PIN gpio_tx_en_o[1]
    DIRECTION OUTPUT ;
    USE SIGNAL ;
    ANTENNADIFFAREA 0.702900 ;
    PORT
      LAYER met2 ;
        RECT 2681.890 4248.960 2682.170 4249.240 ;
    END
  END gpio_tx_en_o[1]
  PIN gpio_tx_en_o[2]
    DIRECTION OUTPUT ;
    USE SIGNAL ;
    ANTENNADIFFAREA 0.702900 ;
    PORT
      LAYER met2 ;
        RECT 2669.930 4248.960 2670.210 4249.240 ;
    END
  END gpio_tx_en_o[2]
  PIN gpio_tx_en_o[3]
    DIRECTION OUTPUT ;
    USE SIGNAL ;
    ANTENNADIFFAREA 0.702900 ;
    PORT
      LAYER met2 ;
        RECT 2669.010 4248.960 2669.290 4249.240 ;
    END
  END gpio_tx_en_o[3]
  PIN gpio_tx_en_o[4]
    DIRECTION OUTPUT ;
    USE SIGNAL ;
    ANTENNADIFFAREA 0.702900 ;
    PORT
      LAYER met2 ;
        RECT 2620.250 4248.960 2620.530 4249.240 ;
    END
  END gpio_tx_en_o[4]
  PIN gpio_tx_en_o[5]
    DIRECTION OUTPUT ;
    USE SIGNAL ;
    ANTENNADIFFAREA 0.702900 ;
    PORT
      LAYER met2 ;
        RECT 2618.410 4248.960 2618.690 4249.240 ;
    END
  END gpio_tx_en_o[5]
  PIN gpio_tx_en_o[6]
    DIRECTION OUTPUT ;
    USE SIGNAL ;
    ANTENNADIFFAREA 0.702900 ;
    PORT
      LAYER met2 ;
        RECT 2624.850 4248.960 2625.130 4249.240 ;
    END
  END gpio_tx_en_o[6]
  PIN gpio_tx_en_o[7]
    DIRECTION OUTPUT ;
    USE SIGNAL ;
    ANTENNADIFFAREA 0.702900 ;
    PORT
      LAYER met2 ;
        RECT 2632.210 4248.960 2632.490 4249.240 ;
    END
  END gpio_tx_en_o[7]
  PIN gpio_tx_en_o[8]
    DIRECTION OUTPUT ;
    USE SIGNAL ;
    ANTENNADIFFAREA 0.702900 ;
    PORT
      LAYER met2 ;
        RECT 2514.450 4248.960 2514.730 4249.240 ;
    END
  END gpio_tx_en_o[8]
  PIN gpio_tx_en_o[9]
    DIRECTION OUTPUT ;
    USE SIGNAL ;
    ANTENNADIFFAREA 0.702900 ;
    PORT
      LAYER met2 ;
        RECT 2501.570 4248.960 2501.850 4249.240 ;
    END
  END gpio_tx_en_o[9]
  PIN i2c_scl_i
    DIRECTION INPUT ;
    USE SIGNAL ;
    ANTENNAGATEAREA 0.126000 ;
    PORT
      LAYER met2 ;
        RECT 2784.930 4248.960 2785.210 4249.240 ;
    END
  END i2c_scl_i
  PIN i2c_scl_o
    DIRECTION OUTPUT ;
    USE SIGNAL ;
    PORT
      LAYER met3 ;
        RECT 0.000 1376.360 0.600 1376.960 ;
    END
  END i2c_scl_o
  PIN i2c_scl_oe
    DIRECTION OUTPUT ;
    USE SIGNAL ;
    ANTENNADIFFAREA 0.702900 ;
    PORT
      LAYER met2 ;
        RECT 2830.930 4248.960 2831.210 4249.240 ;
    END
  END i2c_scl_oe
  PIN i2c_sda_i
    DIRECTION INPUT ;
    USE SIGNAL ;
    ANTENNAGATEAREA 0.126000 ;
    PORT
      LAYER met2 ;
        RECT 2857.610 4248.960 2857.890 4249.240 ;
    END
  END i2c_sda_i
  PIN i2c_sda_o
    DIRECTION OUTPUT ;
    USE SIGNAL ;
    PORT
      LAYER met3 ;
        RECT 0.000 1328.760 0.600 1329.360 ;
    END
  END i2c_sda_o
  PIN i2c_sda_oe
    DIRECTION OUTPUT ;
    USE SIGNAL ;
    ANTENNAGATEAREA 0.126000 ;
    ANTENNADIFFAREA 0.429000 ;
    PORT
      LAYER met2 ;
        RECT 2827.250 4248.960 2827.530 4249.240 ;
    END
  END i2c_sda_oe
  PIN jtag_tck
    DIRECTION INPUT ;
    USE SIGNAL ;
    ANTENNAGATEAREA 1.286700 ;
    ANTENNADIFFAREA 0.434700 ;
    PORT
      LAYER met2 ;
        RECT 2358.050 4248.960 2358.330 4249.240 ;
    END
  END jtag_tck
  PIN jtag_tdi
    DIRECTION INPUT ;
    USE SIGNAL ;
    ANTENNAGATEAREA 0.159000 ;
    PORT
      LAYER met2 ;
        RECT 2174.050 4248.960 2174.330 4249.240 ;
    END
  END jtag_tdi
  PIN jtag_tdo
    DIRECTION OUTPUT ;
    USE SIGNAL ;
    ANTENNADIFFAREA 0.702900 ;
    PORT
      LAYER met2 ;
        RECT 2187.850 4248.960 2188.130 4249.240 ;
    END
  END jtag_tdo
  PIN jtag_tms
    DIRECTION INPUT ;
    USE SIGNAL ;
    ANTENNAGATEAREA 0.247500 ;
    PORT
      LAYER met2 ;
        RECT 2173.130 4248.960 2173.410 4249.240 ;
    END
  END jtag_tms
  PIN jtag_trst_n
    DIRECTION INPUT ;
    USE SIGNAL ;
    ANTENNAGATEAREA 0.247500 ;
    PORT
      LAYER met2 ;
        RECT 2357.130 4248.960 2357.410 4249.240 ;
    END
  END jtag_trst_n
  PIN qspi_cs_n
    DIRECTION OUTPUT ;
    USE SIGNAL ;
    ANTENNADIFFAREA 0.702900 ;
    PORT
      LAYER met3 ;
        RECT 3831.800 2618.040 3832.400 2618.640 ;
    END
  END qspi_cs_n
  PIN qspi_io_i[0]
    DIRECTION INPUT ;
    USE SIGNAL ;
    ANTENNAGATEAREA 0.126000 ;
    PORT
      LAYER met3 ;
        RECT 3831.800 2356.920 3832.400 2357.520 ;
    END
  END qspi_io_i[0]
  PIN qspi_io_i[1]
    DIRECTION INPUT ;
    USE SIGNAL ;
    ANTENNAGATEAREA 0.126000 ;
    PORT
      LAYER met3 ;
        RECT 3831.800 2358.280 3832.400 2358.880 ;
    END
  END qspi_io_i[1]
  PIN qspi_io_i[2]
    DIRECTION INPUT ;
    USE SIGNAL ;
    ANTENNAGATEAREA 0.126000 ;
    PORT
      LAYER met3 ;
        RECT 3831.800 2359.640 3832.400 2360.240 ;
    END
  END qspi_io_i[2]
  PIN qspi_io_i[3]
    DIRECTION INPUT ;
    USE SIGNAL ;
    ANTENNAGATEAREA 0.126000 ;
    PORT
      LAYER met3 ;
        RECT 3831.800 2449.400 3832.400 2450.000 ;
    END
  END qspi_io_i[3]
  PIN qspi_io_o[0]
    DIRECTION OUTPUT ;
    USE SIGNAL ;
    ANTENNADIFFAREA 0.702900 ;
    PORT
      LAYER met3 ;
        RECT 3831.800 2569.080 3832.400 2569.680 ;
    END
  END qspi_io_o[0]
  PIN qspi_io_o[1]
    DIRECTION OUTPUT ;
    USE SIGNAL ;
    ANTENNADIFFAREA 0.702900 ;
    PORT
      LAYER met3 ;
        RECT 3831.800 2567.720 3832.400 2568.320 ;
    END
  END qspi_io_o[1]
  PIN qspi_io_o[2]
    DIRECTION OUTPUT ;
    USE SIGNAL ;
    ANTENNADIFFAREA 0.702900 ;
    PORT
      LAYER met3 ;
        RECT 3831.800 2555.480 3832.400 2556.080 ;
    END
  END qspi_io_o[2]
  PIN qspi_io_o[3]
    DIRECTION OUTPUT ;
    USE SIGNAL ;
    ANTENNADIFFAREA 0.702900 ;
    PORT
      LAYER met3 ;
        RECT 3831.800 2554.120 3832.400 2554.720 ;
    END
  END qspi_io_o[3]
  PIN qspi_io_oe[0]
    DIRECTION OUTPUT ;
    USE SIGNAL ;
    ANTENNADIFFAREA 0.702900 ;
    PORT
      LAYER met3 ;
        RECT 3831.800 2646.600 3832.400 2647.200 ;
    END
  END qspi_io_oe[0]
  PIN qspi_io_oe[1]
    DIRECTION OUTPUT ;
    USE SIGNAL ;
    ANTENNADIFFAREA 0.702900 ;
    PORT
      LAYER met3 ;
        RECT 3831.800 2647.960 3832.400 2648.560 ;
    END
  END qspi_io_oe[1]
  PIN qspi_io_oe[2]
    DIRECTION OUTPUT ;
    USE SIGNAL ;
    ANTENNADIFFAREA 0.702900 ;
    PORT
      LAYER met3 ;
        RECT 3831.800 2643.880 3832.400 2644.480 ;
    END
  END qspi_io_oe[2]
  PIN qspi_io_oe[3]
    DIRECTION OUTPUT ;
    USE SIGNAL ;
    ANTENNADIFFAREA 0.702900 ;
    PORT
      LAYER met3 ;
        RECT 3831.800 2642.520 3832.400 2643.120 ;
    END
  END qspi_io_oe[3]
  PIN qspi_sck
    DIRECTION OUTPUT ;
    USE SIGNAL ;
    ANTENNADIFFAREA 1.336500 ;
    PORT
      LAYER met3 ;
        RECT 3831.800 2586.760 3832.400 2587.360 ;
    END
  END qspi_sck
  PIN rst_ni
    DIRECTION INPUT ;
    USE SIGNAL ;
    ANTENNAGATEAREA 0.247500 ;
    PORT
      LAYER met2 ;
        RECT 946.770 0.000 947.050 0.280 ;
    END
  END rst_ni
  PIN uart1_rxd
    DIRECTION INPUT ;
    USE SIGNAL ;
    ANTENNAGATEAREA 0.213000 ;
    PORT
      LAYER met2 ;
        RECT 2606.450 4248.960 2606.730 4249.240 ;
    END
  END uart1_rxd
  PIN uart1_txd
    DIRECTION OUTPUT ;
    USE SIGNAL ;
    ANTENNADIFFAREA 0.702900 ;
    PORT
      LAYER met2 ;
        RECT 2535.610 4248.960 2535.890 4249.240 ;
    END
  END uart1_txd
  PIN uart2_rxd
    DIRECTION INPUT ;
    USE SIGNAL ;
    ANTENNAGATEAREA 0.213000 ;
    PORT
      LAYER met2 ;
        RECT 2036.970 4248.960 2037.250 4249.240 ;
    END
  END uart2_rxd
  PIN uart2_txd
    DIRECTION OUTPUT ;
    USE SIGNAL ;
    ANTENNADIFFAREA 0.702900 ;
    PORT
      LAYER met2 ;
        RECT 2130.810 4248.960 2131.090 4249.240 ;
    END
  END uart2_txd
  OBS
      LAYER nwell ;
        RECT 5.330 10.795 3826.930 4237.845 ;
      LAYER li1 ;
        RECT 5.520 10.795 3826.740 4237.845 ;
      LAYER met1 ;
        RECT 0.990 0.040 3829.890 4248.260 ;
      LAYER met2 ;
        RECT 1.010 4248.680 2036.690 4248.960 ;
        RECT 2037.530 4248.680 2130.530 4248.960 ;
        RECT 2131.370 4248.680 2172.850 4248.960 ;
        RECT 2173.690 4248.680 2173.770 4248.960 ;
        RECT 2174.610 4248.680 2187.570 4248.960 ;
        RECT 2188.410 4248.680 2356.850 4248.960 ;
        RECT 2357.690 4248.680 2357.770 4248.960 ;
        RECT 2358.610 4248.680 2483.810 4248.960 ;
        RECT 2484.650 4248.680 2485.650 4248.960 ;
        RECT 2486.490 4248.680 2501.290 4248.960 ;
        RECT 2502.130 4248.680 2504.970 4248.960 ;
        RECT 2505.810 4248.680 2509.570 4248.960 ;
        RECT 2510.410 4248.680 2514.170 4248.960 ;
        RECT 2515.010 4248.680 2525.210 4248.960 ;
        RECT 2526.050 4248.680 2526.130 4248.960 ;
        RECT 2526.970 4248.680 2534.410 4248.960 ;
        RECT 2535.250 4248.680 2535.330 4248.960 ;
        RECT 2536.170 4248.680 2536.250 4248.960 ;
        RECT 2537.090 4248.680 2540.850 4248.960 ;
        RECT 2541.690 4248.680 2541.770 4248.960 ;
        RECT 2542.610 4248.680 2552.810 4248.960 ;
        RECT 2553.650 4248.680 2573.970 4248.960 ;
        RECT 2574.810 4248.680 2575.810 4248.960 ;
        RECT 2576.650 4248.680 2577.650 4248.960 ;
        RECT 2578.490 4248.680 2579.490 4248.960 ;
        RECT 2580.330 4248.680 2590.530 4248.960 ;
        RECT 2591.370 4248.680 2594.210 4248.960 ;
        RECT 2595.050 4248.680 2606.170 4248.960 ;
        RECT 2607.010 4248.680 2608.010 4248.960 ;
        RECT 2608.850 4248.680 2610.770 4248.960 ;
        RECT 2611.610 4248.680 2611.690 4248.960 ;
        RECT 2612.530 4248.680 2614.450 4248.960 ;
        RECT 2615.290 4248.680 2618.130 4248.960 ;
        RECT 2618.970 4248.680 2619.050 4248.960 ;
        RECT 2619.890 4248.680 2619.970 4248.960 ;
        RECT 2620.810 4248.680 2623.650 4248.960 ;
        RECT 2624.490 4248.680 2624.570 4248.960 ;
        RECT 2625.410 4248.680 2626.410 4248.960 ;
        RECT 2627.250 4248.680 2628.250 4248.960 ;
        RECT 2629.090 4248.680 2629.170 4248.960 ;
        RECT 2630.010 4248.680 2631.010 4248.960 ;
        RECT 2631.850 4248.680 2631.930 4248.960 ;
        RECT 2632.770 4248.680 2648.490 4248.960 ;
        RECT 2649.330 4248.680 2649.410 4248.960 ;
        RECT 2650.250 4248.680 2654.930 4248.960 ;
        RECT 2655.770 4248.680 2660.450 4248.960 ;
        RECT 2661.290 4248.680 2665.050 4248.960 ;
        RECT 2665.890 4248.680 2668.730 4248.960 ;
        RECT 2669.570 4248.680 2669.650 4248.960 ;
        RECT 2670.490 4248.680 2674.250 4248.960 ;
        RECT 2675.090 4248.680 2675.170 4248.960 ;
        RECT 2676.010 4248.680 2676.090 4248.960 ;
        RECT 2676.930 4248.680 2677.010 4248.960 ;
        RECT 2677.850 4248.680 2681.610 4248.960 ;
        RECT 2682.450 4248.680 2682.530 4248.960 ;
        RECT 2683.370 4248.680 2711.970 4248.960 ;
        RECT 2712.810 4248.680 2714.730 4248.960 ;
        RECT 2715.570 4248.680 2784.650 4248.960 ;
        RECT 2785.490 4248.680 2826.970 4248.960 ;
        RECT 2827.810 4248.680 2830.650 4248.960 ;
        RECT 2831.490 4248.680 2857.330 4248.960 ;
        RECT 2858.170 4248.680 3829.870 4248.960 ;
        RECT 1.010 0.560 3829.870 4248.680 ;
        RECT 1.010 0.010 250.970 0.560 ;
        RECT 251.810 0.010 946.490 0.560 ;
        RECT 947.330 0.010 3829.870 0.560 ;
      LAYER met3 ;
        RECT 0.600 2648.960 3831.800 4243.025 ;
        RECT 0.600 2646.200 3831.400 2648.960 ;
        RECT 0.600 2644.880 3831.800 2646.200 ;
        RECT 0.600 2642.120 3831.400 2644.880 ;
        RECT 0.600 2619.040 3831.800 2642.120 ;
        RECT 0.600 2617.640 3831.400 2619.040 ;
        RECT 0.600 2587.760 3831.800 2617.640 ;
        RECT 0.600 2586.360 3831.400 2587.760 ;
        RECT 0.600 2570.080 3831.800 2586.360 ;
        RECT 0.600 2567.320 3831.400 2570.080 ;
        RECT 0.600 2556.480 3831.800 2567.320 ;
        RECT 0.600 2553.720 3831.400 2556.480 ;
        RECT 0.600 2450.400 3831.800 2553.720 ;
        RECT 0.600 2449.000 3831.400 2450.400 ;
        RECT 0.600 2360.640 3831.800 2449.000 ;
        RECT 0.600 2356.520 3831.400 2360.640 ;
        RECT 0.600 1377.360 3831.800 2356.520 ;
        RECT 1.000 1375.960 3831.800 1377.360 ;
        RECT 0.600 1329.760 3831.800 1375.960 ;
        RECT 1.000 1328.360 3831.800 1329.760 ;
        RECT 0.600 10.715 3831.800 1328.360 ;
      LAYER met4 ;
        RECT 226.190 3778.520 327.840 4230.785 ;
        RECT 330.240 3778.520 331.140 4230.785 ;
        RECT 333.540 3778.520 481.440 4230.785 ;
        RECT 483.840 3778.520 484.740 4230.785 ;
        RECT 487.140 3778.520 635.040 4230.785 ;
        RECT 637.440 3778.520 638.340 4230.785 ;
        RECT 640.740 3778.520 788.640 4230.785 ;
        RECT 791.040 3778.520 791.940 4230.785 ;
        RECT 794.340 3778.520 942.240 4230.785 ;
        RECT 944.640 3778.520 945.540 4230.785 ;
        RECT 947.940 3778.520 1095.840 4230.785 ;
        RECT 226.190 3303.420 1095.840 3778.520 ;
        RECT 226.190 3302.500 331.140 3303.420 ;
        RECT 226.190 3161.980 327.840 3302.500 ;
        RECT 330.240 3161.980 331.140 3302.500 ;
        RECT 333.540 3302.500 484.740 3303.420 ;
        RECT 333.540 3161.980 481.440 3302.500 ;
        RECT 483.840 3161.980 484.740 3302.500 ;
        RECT 487.140 3161.980 635.040 3303.420 ;
        RECT 637.440 3161.980 638.340 3303.420 ;
        RECT 640.740 3161.980 788.640 3303.420 ;
        RECT 791.040 3161.980 791.940 3303.420 ;
        RECT 794.340 3161.980 942.240 3303.420 ;
        RECT 944.640 3161.980 945.540 3303.420 ;
        RECT 947.940 3161.980 1095.840 3303.420 ;
        RECT 226.190 2686.880 1095.840 3161.980 ;
        RECT 226.190 2685.960 331.140 2686.880 ;
        RECT 226.190 2545.440 327.840 2685.960 ;
        RECT 330.240 2545.440 331.140 2685.960 ;
        RECT 333.540 2685.960 484.740 2686.880 ;
        RECT 333.540 2545.440 481.440 2685.960 ;
        RECT 483.840 2545.440 484.740 2685.960 ;
        RECT 487.140 2545.440 635.040 2686.880 ;
        RECT 637.440 2545.440 638.340 2686.880 ;
        RECT 640.740 2545.440 788.640 2686.880 ;
        RECT 791.040 2545.440 791.940 2686.880 ;
        RECT 794.340 2545.440 942.240 2686.880 ;
        RECT 944.640 2545.440 945.540 2686.880 ;
        RECT 947.940 2545.440 1095.840 2686.880 ;
        RECT 226.190 2070.340 1095.840 2545.440 ;
        RECT 226.190 2069.420 331.140 2070.340 ;
        RECT 226.190 1928.900 327.840 2069.420 ;
        RECT 330.240 1928.900 331.140 2069.420 ;
        RECT 333.540 2069.420 484.740 2070.340 ;
        RECT 333.540 1928.900 481.440 2069.420 ;
        RECT 483.840 1928.900 484.740 2069.420 ;
        RECT 487.140 1928.900 635.040 2070.340 ;
        RECT 637.440 1928.900 638.340 2070.340 ;
        RECT 640.740 1928.900 788.640 2070.340 ;
        RECT 791.040 1928.900 791.940 2070.340 ;
        RECT 794.340 1928.900 942.240 2070.340 ;
        RECT 944.640 1928.900 945.540 2070.340 ;
        RECT 947.940 1928.900 1095.840 2070.340 ;
        RECT 226.190 1453.800 1095.840 1928.900 ;
        RECT 226.190 1452.880 331.140 1453.800 ;
        RECT 226.190 1312.360 327.840 1452.880 ;
        RECT 330.240 1312.360 331.140 1452.880 ;
        RECT 333.540 1452.880 484.740 1453.800 ;
        RECT 333.540 1312.360 481.440 1452.880 ;
        RECT 483.840 1312.360 484.740 1452.880 ;
        RECT 487.140 1312.360 635.040 1453.800 ;
        RECT 637.440 1312.360 638.340 1453.800 ;
        RECT 640.740 1312.360 788.640 1453.800 ;
        RECT 791.040 1312.360 791.940 1453.800 ;
        RECT 794.340 1312.360 942.240 1453.800 ;
        RECT 944.640 1312.360 945.540 1453.800 ;
        RECT 947.940 1312.360 1095.840 1453.800 ;
        RECT 226.190 837.260 1095.840 1312.360 ;
        RECT 226.190 836.340 331.140 837.260 ;
        RECT 226.190 695.820 327.840 836.340 ;
        RECT 330.240 695.820 331.140 836.340 ;
        RECT 333.540 836.340 484.740 837.260 ;
        RECT 333.540 695.820 481.440 836.340 ;
        RECT 483.840 695.820 484.740 836.340 ;
        RECT 487.140 695.820 635.040 837.260 ;
        RECT 637.440 695.820 638.340 837.260 ;
        RECT 640.740 695.820 788.640 837.260 ;
        RECT 791.040 695.820 791.940 837.260 ;
        RECT 794.340 695.820 942.240 837.260 ;
        RECT 944.640 695.820 945.540 837.260 ;
        RECT 947.940 695.820 1095.840 837.260 ;
        RECT 226.190 220.720 1095.840 695.820 ;
        RECT 226.190 219.800 331.140 220.720 ;
        RECT 226.190 200.095 327.840 219.800 ;
        RECT 330.240 200.095 331.140 219.800 ;
        RECT 333.540 219.800 484.740 220.720 ;
        RECT 333.540 200.095 481.440 219.800 ;
        RECT 483.840 200.095 484.740 219.800 ;
        RECT 487.140 200.095 635.040 220.720 ;
        RECT 637.440 200.095 638.340 220.720 ;
        RECT 640.740 200.095 788.640 220.720 ;
        RECT 791.040 200.095 791.940 220.720 ;
        RECT 794.340 200.095 942.240 220.720 ;
        RECT 944.640 200.095 945.540 220.720 ;
        RECT 947.940 200.095 1095.840 220.720 ;
        RECT 1098.240 200.095 1099.140 4230.785 ;
        RECT 1101.540 3778.520 1249.440 4230.785 ;
        RECT 1251.840 3778.520 1252.740 4230.785 ;
        RECT 1255.140 3778.520 1403.040 4230.785 ;
        RECT 1405.440 3778.520 1406.340 4230.785 ;
        RECT 1408.740 3778.520 1556.640 4230.785 ;
        RECT 1559.040 3778.520 1559.940 4230.785 ;
        RECT 1562.340 3778.520 1710.240 4230.785 ;
        RECT 1712.640 3778.520 1713.540 4230.785 ;
        RECT 1715.940 3778.520 1863.840 4230.785 ;
        RECT 1101.540 3303.420 1863.840 3778.520 ;
        RECT 1101.540 3161.980 1249.440 3303.420 ;
        RECT 1251.840 3302.720 1406.340 3303.420 ;
        RECT 1251.840 3161.980 1252.740 3302.720 ;
        RECT 1255.140 3302.500 1406.340 3302.720 ;
        RECT 1255.140 3161.980 1403.040 3302.500 ;
        RECT 1405.440 3161.980 1406.340 3302.500 ;
        RECT 1408.740 3161.980 1556.640 3303.420 ;
        RECT 1559.040 3161.980 1559.940 3303.420 ;
        RECT 1562.340 3161.980 1710.240 3303.420 ;
        RECT 1712.640 3161.980 1713.540 3303.420 ;
        RECT 1715.940 3161.980 1863.840 3303.420 ;
        RECT 1101.540 2686.880 1863.840 3161.980 ;
        RECT 1101.540 2545.440 1249.440 2686.880 ;
        RECT 1251.840 2685.960 1406.340 2686.880 ;
        RECT 1251.840 2545.440 1252.740 2685.960 ;
        RECT 1255.140 2545.440 1403.040 2685.960 ;
        RECT 1405.440 2545.440 1406.340 2685.960 ;
        RECT 1408.740 2545.440 1556.640 2686.880 ;
        RECT 1559.040 2545.440 1559.940 2686.880 ;
        RECT 1562.340 2545.440 1710.240 2686.880 ;
        RECT 1712.640 2545.440 1713.540 2686.880 ;
        RECT 1715.940 2545.440 1863.840 2686.880 ;
        RECT 1101.540 2070.340 1863.840 2545.440 ;
        RECT 1101.540 1928.900 1249.440 2070.340 ;
        RECT 1251.840 2069.420 1406.340 2070.340 ;
        RECT 1251.840 1928.900 1252.740 2069.420 ;
        RECT 1255.140 1928.900 1403.040 2069.420 ;
        RECT 1405.440 1928.900 1406.340 2069.420 ;
        RECT 1408.740 1928.900 1556.640 2070.340 ;
        RECT 1559.040 1928.900 1559.940 2070.340 ;
        RECT 1562.340 1928.900 1710.240 2070.340 ;
        RECT 1712.640 1928.900 1713.540 2070.340 ;
        RECT 1715.940 1928.900 1863.840 2070.340 ;
        RECT 1101.540 1453.800 1863.840 1928.900 ;
        RECT 1101.540 1312.360 1249.440 1453.800 ;
        RECT 1251.840 1453.120 1406.340 1453.800 ;
        RECT 1251.840 1312.360 1252.740 1453.120 ;
        RECT 1255.140 1452.880 1406.340 1453.120 ;
        RECT 1255.140 1312.360 1403.040 1452.880 ;
        RECT 1405.440 1312.360 1406.340 1452.880 ;
        RECT 1408.740 1312.360 1556.640 1453.800 ;
        RECT 1559.040 1312.360 1559.940 1453.800 ;
        RECT 1562.340 1312.360 1710.240 1453.800 ;
        RECT 1712.640 1312.360 1713.540 1453.800 ;
        RECT 1715.940 1312.360 1863.840 1453.800 ;
        RECT 1101.540 837.260 1863.840 1312.360 ;
        RECT 1101.540 695.820 1249.440 837.260 ;
        RECT 1251.840 836.340 1406.340 837.260 ;
        RECT 1251.840 695.820 1252.740 836.340 ;
        RECT 1255.140 695.820 1403.040 836.340 ;
        RECT 1405.440 695.820 1406.340 836.340 ;
        RECT 1408.740 695.820 1556.640 837.260 ;
        RECT 1559.040 695.820 1559.940 837.260 ;
        RECT 1562.340 695.820 1710.240 837.260 ;
        RECT 1712.640 695.820 1713.540 837.260 ;
        RECT 1715.940 695.820 1863.840 837.260 ;
        RECT 1101.540 220.720 1863.840 695.820 ;
        RECT 1101.540 200.095 1249.440 220.720 ;
        RECT 1251.840 219.800 1406.340 220.720 ;
        RECT 1251.840 200.095 1252.740 219.800 ;
        RECT 1255.140 200.095 1403.040 219.800 ;
        RECT 1405.440 200.095 1406.340 219.800 ;
        RECT 1408.740 200.095 1556.640 220.720 ;
        RECT 1559.040 200.095 1559.940 220.720 ;
        RECT 1562.340 200.095 1710.240 220.720 ;
        RECT 1712.640 200.095 1713.540 220.720 ;
        RECT 1715.940 200.095 1863.840 220.720 ;
        RECT 1866.240 200.095 1867.140 4230.785 ;
        RECT 1869.540 3778.520 2017.440 4230.785 ;
        RECT 2019.840 3778.520 2020.740 4230.785 ;
        RECT 2023.140 3779.440 2171.040 4230.785 ;
        RECT 2173.440 3779.440 2174.340 4230.785 ;
        RECT 2023.140 3778.520 2174.340 3779.440 ;
        RECT 2176.740 3778.520 2324.640 4230.785 ;
        RECT 2327.040 3778.520 2327.940 4230.785 ;
        RECT 2330.340 3778.520 2478.240 4230.785 ;
        RECT 2480.640 3779.440 2481.540 4230.785 ;
        RECT 2483.940 3779.440 2631.840 4230.785 ;
        RECT 2480.640 3778.520 2631.840 3779.440 ;
        RECT 2634.240 3778.520 2635.140 4230.785 ;
        RECT 2637.540 3778.520 2785.440 4230.785 ;
        RECT 1869.540 3303.420 2785.440 3778.520 ;
        RECT 1869.540 3161.980 2017.440 3303.420 ;
        RECT 2019.840 3161.980 2020.740 3303.420 ;
        RECT 2023.140 3302.500 2174.340 3303.420 ;
        RECT 2023.140 3162.720 2171.040 3302.500 ;
        RECT 2173.440 3162.720 2174.340 3302.500 ;
        RECT 2023.140 3161.980 2174.340 3162.720 ;
        RECT 2176.740 3161.980 2324.640 3303.420 ;
        RECT 2327.040 3161.980 2327.940 3303.420 ;
        RECT 2330.340 3161.980 2478.240 3303.420 ;
        RECT 2480.640 3302.720 2635.140 3303.420 ;
        RECT 2480.640 3162.900 2481.540 3302.720 ;
        RECT 2483.940 3302.500 2635.140 3302.720 ;
        RECT 2483.940 3162.900 2631.840 3302.500 ;
        RECT 2480.640 3161.980 2631.840 3162.900 ;
        RECT 2634.240 3161.980 2635.140 3302.500 ;
        RECT 2637.540 3161.980 2785.440 3303.420 ;
        RECT 1869.540 2686.880 2785.440 3161.980 ;
        RECT 1869.540 2545.440 2017.440 2686.880 ;
        RECT 2019.840 2545.440 2020.740 2686.880 ;
        RECT 2023.140 2685.960 2174.340 2686.880 ;
        RECT 2023.140 2546.360 2171.040 2685.960 ;
        RECT 2173.440 2546.360 2174.340 2685.960 ;
        RECT 2023.140 2545.440 2174.340 2546.360 ;
        RECT 2176.740 2545.440 2324.640 2686.880 ;
        RECT 2327.040 2545.440 2327.940 2686.880 ;
        RECT 2330.340 2545.440 2478.240 2686.880 ;
        RECT 2480.640 2685.960 2635.140 2686.880 ;
        RECT 2480.640 2546.360 2481.540 2685.960 ;
        RECT 2483.940 2546.360 2631.840 2685.960 ;
        RECT 2480.640 2545.440 2631.840 2546.360 ;
        RECT 2634.240 2545.440 2635.140 2685.960 ;
        RECT 2637.540 2545.440 2785.440 2686.880 ;
        RECT 1869.540 2070.340 2785.440 2545.440 ;
        RECT 1869.540 1928.900 2017.440 2070.340 ;
        RECT 2019.840 1928.900 2020.740 2070.340 ;
        RECT 2023.140 2069.420 2174.340 2070.340 ;
        RECT 2023.140 1929.820 2171.040 2069.420 ;
        RECT 2173.440 1929.820 2174.340 2069.420 ;
        RECT 2023.140 1928.900 2174.340 1929.820 ;
        RECT 2176.740 1928.900 2324.640 2070.340 ;
        RECT 2327.040 1928.900 2327.940 2070.340 ;
        RECT 2330.340 1928.900 2478.240 2070.340 ;
        RECT 2480.640 2069.420 2635.140 2070.340 ;
        RECT 2480.640 1929.820 2481.540 2069.420 ;
        RECT 2483.940 1929.820 2631.840 2069.420 ;
        RECT 2480.640 1928.900 2631.840 1929.820 ;
        RECT 2634.240 1928.900 2635.140 2069.420 ;
        RECT 2637.540 1928.900 2785.440 2070.340 ;
        RECT 1869.540 1453.800 2785.440 1928.900 ;
        RECT 1869.540 1312.360 2017.440 1453.800 ;
        RECT 2019.840 1312.360 2020.740 1453.800 ;
        RECT 2023.140 1452.880 2174.340 1453.800 ;
        RECT 2023.140 1313.120 2171.040 1452.880 ;
        RECT 2173.440 1313.120 2174.340 1452.880 ;
        RECT 2023.140 1312.360 2174.340 1313.120 ;
        RECT 2176.740 1312.360 2324.640 1453.800 ;
        RECT 2327.040 1312.360 2327.940 1453.800 ;
        RECT 2330.340 1312.360 2478.240 1453.800 ;
        RECT 2480.640 1453.120 2635.140 1453.800 ;
        RECT 2480.640 1313.280 2481.540 1453.120 ;
        RECT 2483.940 1452.880 2635.140 1453.120 ;
        RECT 2483.940 1313.280 2631.840 1452.880 ;
        RECT 2480.640 1312.360 2631.840 1313.280 ;
        RECT 2634.240 1312.360 2635.140 1452.880 ;
        RECT 2637.540 1312.360 2785.440 1453.800 ;
        RECT 1869.540 837.260 2785.440 1312.360 ;
        RECT 1869.540 695.820 2017.440 837.260 ;
        RECT 2019.840 695.820 2020.740 837.260 ;
        RECT 2023.140 836.340 2174.340 837.260 ;
        RECT 2023.140 696.740 2171.040 836.340 ;
        RECT 2173.440 696.740 2174.340 836.340 ;
        RECT 2023.140 695.820 2174.340 696.740 ;
        RECT 2176.740 695.820 2324.640 837.260 ;
        RECT 2327.040 695.820 2327.940 837.260 ;
        RECT 2330.340 695.820 2478.240 837.260 ;
        RECT 2480.640 836.340 2635.140 837.260 ;
        RECT 2480.640 696.740 2481.540 836.340 ;
        RECT 2483.940 696.740 2631.840 836.340 ;
        RECT 2480.640 695.820 2631.840 696.740 ;
        RECT 2634.240 695.820 2635.140 836.340 ;
        RECT 2637.540 695.820 2785.440 837.260 ;
        RECT 1869.540 220.720 2785.440 695.820 ;
        RECT 1869.540 200.095 2017.440 220.720 ;
        RECT 2019.840 200.095 2020.740 220.720 ;
        RECT 2023.140 219.800 2174.340 220.720 ;
        RECT 2023.140 200.095 2171.040 219.800 ;
        RECT 2173.440 200.095 2174.340 219.800 ;
        RECT 2176.740 200.095 2324.640 220.720 ;
        RECT 2327.040 200.095 2327.940 220.720 ;
        RECT 2330.340 200.095 2478.240 220.720 ;
        RECT 2480.640 219.800 2635.140 220.720 ;
        RECT 2480.640 200.095 2481.540 219.800 ;
        RECT 2483.940 200.095 2631.840 219.800 ;
        RECT 2634.240 200.095 2635.140 219.800 ;
        RECT 2637.540 200.095 2785.440 220.720 ;
        RECT 2787.840 200.095 2788.740 4230.785 ;
        RECT 2791.140 3778.520 2939.040 4230.785 ;
        RECT 2941.440 3778.520 2942.340 4230.785 ;
        RECT 2944.740 3778.520 3092.640 4230.785 ;
        RECT 3095.040 3778.520 3095.940 4230.785 ;
        RECT 3098.340 3778.520 3246.240 4230.785 ;
        RECT 3248.640 3778.520 3249.540 4230.785 ;
        RECT 3251.940 3778.520 3399.840 4230.785 ;
        RECT 3402.240 3779.440 3403.140 4230.785 ;
        RECT 3405.540 3779.440 3553.440 4230.785 ;
        RECT 3555.840 3779.440 3556.740 4230.785 ;
        RECT 3402.240 3778.520 3556.740 3779.440 ;
        RECT 3559.140 3778.520 3707.040 4230.785 ;
        RECT 2791.140 3303.420 3707.040 3778.520 ;
        RECT 2791.140 3161.980 2939.040 3303.420 ;
        RECT 2941.440 3161.980 2942.340 3303.420 ;
        RECT 2944.740 3161.980 3092.640 3303.420 ;
        RECT 3095.040 3302.720 3246.240 3303.420 ;
        RECT 3095.040 3161.980 3095.940 3302.720 ;
        RECT 3098.340 3161.980 3246.240 3302.720 ;
        RECT 3248.640 3161.980 3249.540 3303.420 ;
        RECT 3251.940 3161.980 3399.840 3303.420 ;
        RECT 3402.240 3302.720 3553.440 3303.420 ;
        RECT 3402.240 3162.900 3403.140 3302.720 ;
        RECT 3405.540 3162.900 3553.440 3302.720 ;
        RECT 3402.240 3162.720 3553.440 3162.900 ;
        RECT 3555.840 3162.720 3556.740 3303.420 ;
        RECT 3402.240 3161.980 3556.740 3162.720 ;
        RECT 3559.140 3161.980 3707.040 3303.420 ;
        RECT 2791.140 2686.880 3707.040 3161.980 ;
        RECT 2791.140 1928.900 2939.040 2686.880 ;
        RECT 2941.440 1928.900 2942.340 2686.880 ;
        RECT 2944.740 1928.900 3092.640 2686.880 ;
        RECT 3095.040 2685.960 3246.240 2686.880 ;
        RECT 3095.040 1928.900 3095.940 2685.960 ;
        RECT 3098.340 1928.900 3246.240 2685.960 ;
        RECT 3248.640 1928.900 3249.540 2686.880 ;
        RECT 3251.940 1928.900 3399.840 2686.880 ;
        RECT 3402.240 2685.960 3553.440 2686.880 ;
        RECT 3402.240 1929.820 3403.140 2685.960 ;
        RECT 3405.540 1929.820 3553.440 2685.960 ;
        RECT 3555.840 1929.820 3556.740 2686.880 ;
        RECT 3402.240 1928.900 3556.740 1929.820 ;
        RECT 3559.140 1928.900 3707.040 2686.880 ;
        RECT 2791.140 1453.800 3707.040 1928.900 ;
        RECT 2791.140 1312.360 2939.040 1453.800 ;
        RECT 2941.440 1312.360 2942.340 1453.800 ;
        RECT 2944.740 1312.360 3092.640 1453.800 ;
        RECT 3095.040 1453.120 3246.240 1453.800 ;
        RECT 3095.040 1312.360 3095.940 1453.120 ;
        RECT 3098.340 1312.360 3246.240 1453.120 ;
        RECT 3248.640 1312.360 3249.540 1453.800 ;
        RECT 3251.940 1312.360 3399.840 1453.800 ;
        RECT 3402.240 1453.120 3553.440 1453.800 ;
        RECT 3402.240 1313.280 3403.140 1453.120 ;
        RECT 3405.540 1313.280 3553.440 1453.120 ;
        RECT 3402.240 1313.120 3553.440 1313.280 ;
        RECT 3555.840 1313.120 3556.740 1453.800 ;
        RECT 3402.240 1312.360 3556.740 1313.120 ;
        RECT 3559.140 1312.360 3707.040 1453.800 ;
        RECT 2791.140 837.260 3707.040 1312.360 ;
        RECT 2791.140 695.820 2939.040 837.260 ;
        RECT 2941.440 695.820 2942.340 837.260 ;
        RECT 2944.740 695.820 3092.640 837.260 ;
        RECT 3095.040 836.340 3246.240 837.260 ;
        RECT 3095.040 695.820 3095.940 836.340 ;
        RECT 3098.340 695.820 3246.240 836.340 ;
        RECT 3248.640 695.820 3249.540 837.260 ;
        RECT 3251.940 695.820 3399.840 837.260 ;
        RECT 3402.240 836.340 3553.440 837.260 ;
        RECT 3402.240 696.740 3403.140 836.340 ;
        RECT 3405.540 696.740 3553.440 836.340 ;
        RECT 3555.840 696.740 3556.740 837.260 ;
        RECT 3402.240 695.820 3556.740 696.740 ;
        RECT 3559.140 695.820 3707.040 837.260 ;
        RECT 2791.140 220.720 3707.040 695.820 ;
        RECT 2791.140 200.095 2939.040 220.720 ;
        RECT 2941.440 200.095 2942.340 220.720 ;
        RECT 2944.740 200.095 3092.640 220.720 ;
        RECT 3095.040 219.800 3246.240 220.720 ;
        RECT 3095.040 200.095 3095.940 219.800 ;
        RECT 3098.340 200.095 3246.240 219.800 ;
        RECT 3248.640 200.095 3249.540 220.720 ;
        RECT 3251.940 200.095 3399.840 220.720 ;
        RECT 3402.240 219.800 3553.440 220.720 ;
        RECT 3402.240 200.095 3403.140 219.800 ;
        RECT 3405.540 200.095 3553.440 219.800 ;
        RECT 3555.840 200.095 3556.740 220.720 ;
        RECT 3559.140 200.095 3707.040 220.720 ;
        RECT 3709.440 200.095 3710.340 4230.785 ;
        RECT 3712.740 200.095 3742.265 4230.785 ;
      LAYER met5 ;
        RECT 225.980 4015.910 3591.100 4133.500 ;
        RECT 225.980 3862.730 3591.100 4007.810 ;
        RECT 225.980 3709.550 3591.100 3854.630 ;
        RECT 225.980 3556.370 3591.100 3701.450 ;
        RECT 225.980 3403.190 3591.100 3548.270 ;
        RECT 225.980 3250.010 3591.100 3395.090 ;
        RECT 225.980 3096.830 3591.100 3241.910 ;
        RECT 225.980 2943.650 3591.100 3088.730 ;
        RECT 225.980 2790.470 3591.100 2935.550 ;
        RECT 225.980 2637.290 3591.100 2782.370 ;
        RECT 225.980 2484.110 3591.100 2629.190 ;
        RECT 225.980 2330.930 3591.100 2476.010 ;
        RECT 225.980 2177.750 3591.100 2322.830 ;
        RECT 225.980 2024.570 3591.100 2169.650 ;
        RECT 225.980 1871.390 3591.100 2016.470 ;
        RECT 225.980 1718.210 3591.100 1863.290 ;
        RECT 225.980 1565.030 3591.100 1710.110 ;
        RECT 225.980 1411.850 3591.100 1556.930 ;
        RECT 225.980 1258.670 3591.100 1403.750 ;
        RECT 225.980 1105.490 3591.100 1250.570 ;
        RECT 225.980 952.310 3591.100 1097.390 ;
        RECT 225.980 799.130 3591.100 944.210 ;
        RECT 225.980 645.950 3591.100 791.030 ;
        RECT 225.980 492.770 3591.100 637.850 ;
        RECT 225.980 339.590 3591.100 484.670 ;
        RECT 225.980 238.900 3591.100 331.490 ;
  END
END soc_top
END LIBRARY

